VERSION 5.7 ;
  NOWIREEXTENSIONATPIN ON ;
  DIVIDERCHAR "/" ;
  BUSBITCHARS "[]" ;
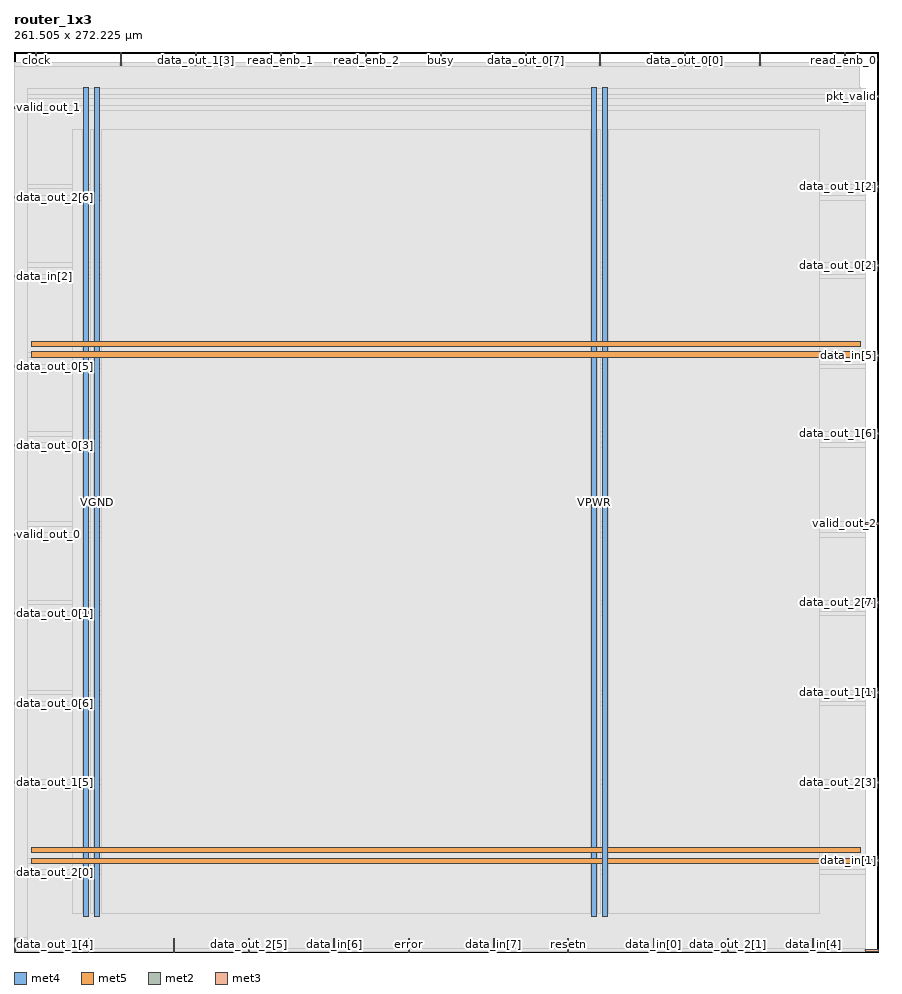
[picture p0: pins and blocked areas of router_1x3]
MACRO router_1x3
  CLASS BLOCK ;
  FOREIGN router_1x3 ;
  ORIGIN 0.000 0.000 ;
  SIZE 261.505 BY 272.225 ;
  PIN VGND
    DIRECTION INOUT ;
    USE GROUND ;
    PORT
      LAYER met4 ;
        RECT 24.340 10.640 25.940 261.360 ;
    END
    PORT
      LAYER met4 ;
        RECT 177.940 10.640 179.540 261.360 ;
    END
    PORT
      LAYER met5 ;
        RECT 5.280 30.030 256.000 31.630 ;
    END
    PORT
      LAYER met5 ;
        RECT 5.280 183.210 256.000 184.810 ;
    END
  END VGND
  PIN VPWR
    DIRECTION INOUT ;
    USE POWER ;
    PORT
      LAYER met4 ;
        RECT 21.040 10.640 22.640 261.360 ;
    END
    PORT
      LAYER met4 ;
        RECT 174.640 10.640 176.240 261.360 ;
    END
    PORT
      LAYER met5 ;
        RECT 5.280 26.730 256.000 28.330 ;
    END
    PORT
      LAYER met5 ;
        RECT 5.280 179.910 256.000 181.510 ;
    END
  END VPWR
  PIN busy
    DIRECTION OUTPUT TRISTATE ;
    USE SIGNAL ;
    ANTENNADIFFAREA 0.795200 ;
    PORT
      LAYER met2 ;
        RECT 128.890 268.225 129.170 272.225 ;
    END
  END busy
  PIN clock
    DIRECTION INPUT ;
    USE SIGNAL ;
    ANTENNAGATEAREA 0.852000 ;
    PORT
      LAYER met2 ;
        RECT 6.530 268.225 6.810 272.225 ;
    END
  END clock
  PIN data_in[0]
    DIRECTION INPUT ;
    USE SIGNAL ;
    ANTENNAGATEAREA 0.213000 ;
    PORT
      LAYER met2 ;
        RECT 193.290 0.000 193.570 4.000 ;
    END
  END data_in[0]
  PIN data_in[1]
    DIRECTION INPUT ;
    USE SIGNAL ;
    ANTENNAGATEAREA 0.213000 ;
    PORT
      LAYER met3 ;
        RECT 257.505 27.240 261.505 27.840 ;
    END
  END data_in[1]
  PIN data_in[2]
    DIRECTION INPUT ;
    USE SIGNAL ;
    ANTENNAGATEAREA 0.213000 ;
    PORT
      LAYER met3 ;
        RECT 0.000 204.040 4.000 204.640 ;
    END
  END data_in[2]
  PIN data_in[3]
    DIRECTION INPUT ;
    USE SIGNAL ;
    ANTENNAGATEAREA 0.213000 ;
    PORT
      LAYER met3 ;
        RECT 257.505 0.040 261.505 0.640 ;
    END
  END data_in[3]
  PIN data_in[4]
    DIRECTION INPUT ;
    USE SIGNAL ;
    ANTENNAGATEAREA 0.213000 ;
    PORT
      LAYER met2 ;
        RECT 241.590 0.000 241.870 4.000 ;
    END
  END data_in[4]
  PIN data_in[5]
    DIRECTION INPUT ;
    USE SIGNAL ;
    ANTENNAGATEAREA 0.159000 ;
    PORT
      LAYER met3 ;
        RECT 257.505 180.240 261.505 180.840 ;
    END
  END data_in[5]
  PIN data_in[6]
    DIRECTION INPUT ;
    USE SIGNAL ;
    ANTENNAGATEAREA 0.159000 ;
    PORT
      LAYER met2 ;
        RECT 96.690 0.000 96.970 4.000 ;
    END
  END data_in[6]
  PIN data_in[7]
    DIRECTION INPUT ;
    USE SIGNAL ;
    ANTENNAGATEAREA 0.159000 ;
    PORT
      LAYER met2 ;
        RECT 144.990 0.000 145.270 4.000 ;
    END
  END data_in[7]
  PIN data_out_0[0]
    DIRECTION OUTPUT TRISTATE ;
    USE SIGNAL ;
    ANTENNADIFFAREA 0.795200 ;
    PORT
      LAYER met2 ;
        RECT 202.950 268.225 203.230 272.225 ;
    END
  END data_out_0[0]
  PIN data_out_0[1]
    DIRECTION OUTPUT TRISTATE ;
    USE SIGNAL ;
    ANTENNADIFFAREA 0.795200 ;
    PORT
      LAYER met3 ;
        RECT 0.000 102.040 4.000 102.640 ;
    END
  END data_out_0[1]
  PIN data_out_0[2]
    DIRECTION OUTPUT TRISTATE ;
    USE SIGNAL ;
    ANTENNADIFFAREA 0.795200 ;
    PORT
      LAYER met3 ;
        RECT 257.505 207.440 261.505 208.040 ;
    END
  END data_out_0[2]
  PIN data_out_0[3]
    DIRECTION OUTPUT TRISTATE ;
    USE SIGNAL ;
    ANTENNADIFFAREA 0.795200 ;
    PORT
      LAYER met3 ;
        RECT 0.000 153.040 4.000 153.640 ;
    END
  END data_out_0[3]
  PIN data_out_0[4]
    DIRECTION OUTPUT TRISTATE ;
    USE SIGNAL ;
    ANTENNADIFFAREA 0.795200 ;
    PORT
      LAYER met2 ;
        RECT 48.390 0.000 48.670 4.000 ;
    END
  END data_out_0[4]
  PIN data_out_0[5]
    DIRECTION OUTPUT TRISTATE ;
    USE SIGNAL ;
    ANTENNADIFFAREA 0.795200 ;
    PORT
      LAYER met3 ;
        RECT 0.000 176.840 4.000 177.440 ;
    END
  END data_out_0[5]
  PIN data_out_0[6]
    DIRECTION OUTPUT TRISTATE ;
    USE SIGNAL ;
    ANTENNADIFFAREA 0.795200 ;
    PORT
      LAYER met3 ;
        RECT 0.000 74.840 4.000 75.440 ;
    END
  END data_out_0[6]
  PIN data_out_0[7]
    DIRECTION OUTPUT TRISTATE ;
    USE SIGNAL ;
    ANTENNADIFFAREA 0.795200 ;
    PORT
      LAYER met2 ;
        RECT 154.650 268.225 154.930 272.225 ;
    END
  END data_out_0[7]
  PIN data_out_1[0]
    DIRECTION OUTPUT TRISTATE ;
    USE SIGNAL ;
    ANTENNADIFFAREA 0.795200 ;
    PORT
      LAYER met2 ;
        RECT 225.490 268.225 225.770 272.225 ;
    END
  END data_out_1[0]
  PIN data_out_1[1]
    DIRECTION OUTPUT TRISTATE ;
    USE SIGNAL ;
    ANTENNADIFFAREA 0.445500 ;
    PORT
      LAYER met3 ;
        RECT 257.505 78.240 261.505 78.840 ;
    END
  END data_out_1[1]
  PIN data_out_1[2]
    DIRECTION OUTPUT TRISTATE ;
    USE SIGNAL ;
    ANTENNADIFFAREA 0.445500 ;
    PORT
      LAYER met3 ;
        RECT 257.505 231.240 261.505 231.840 ;
    END
  END data_out_1[2]
  PIN data_out_1[3]
    DIRECTION OUTPUT TRISTATE ;
    USE SIGNAL ;
    ANTENNADIFFAREA 0.795200 ;
    PORT
      LAYER met2 ;
        RECT 54.830 268.225 55.110 272.225 ;
    END
  END data_out_1[3]
  PIN data_out_1[4]
    DIRECTION OUTPUT TRISTATE ;
    USE SIGNAL ;
    ANTENNADIFFAREA 0.795200 ;
    PORT
      LAYER met2 ;
        RECT 0.090 0.000 0.370 4.000 ;
    END
  END data_out_1[4]
  PIN data_out_1[5]
    DIRECTION OUTPUT TRISTATE ;
    USE SIGNAL ;
    ANTENNADIFFAREA 0.795200 ;
    PORT
      LAYER met3 ;
        RECT 0.000 51.040 4.000 51.640 ;
    END
  END data_out_1[5]
  PIN data_out_1[6]
    DIRECTION OUTPUT TRISTATE ;
    USE SIGNAL ;
    ANTENNADIFFAREA 0.445500 ;
    PORT
      LAYER met3 ;
        RECT 257.505 156.440 261.505 157.040 ;
    END
  END data_out_1[6]
  PIN data_out_1[7]
    DIRECTION OUTPUT TRISTATE ;
    USE SIGNAL ;
    ANTENNADIFFAREA 0.795200 ;
    PORT
      LAYER met2 ;
        RECT 32.290 268.225 32.570 272.225 ;
    END
  END data_out_1[7]
  PIN data_out_2[0]
    DIRECTION OUTPUT TRISTATE ;
    USE SIGNAL ;
    ANTENNADIFFAREA 0.795200 ;
    PORT
      LAYER met3 ;
        RECT 0.000 23.840 4.000 24.440 ;
    END
  END data_out_2[0]
  PIN data_out_2[1]
    DIRECTION OUTPUT TRISTATE ;
    USE SIGNAL ;
    ANTENNADIFFAREA 0.795200 ;
    PORT
      LAYER met2 ;
        RECT 215.830 0.000 216.110 4.000 ;
    END
  END data_out_2[1]
  PIN data_out_2[2]
    DIRECTION OUTPUT TRISTATE ;
    USE SIGNAL ;
    ANTENNADIFFAREA 0.795200 ;
    PORT
      LAYER met2 ;
        RECT 177.190 268.225 177.470 272.225 ;
    END
  END data_out_2[2]
  PIN data_out_2[3]
    DIRECTION OUTPUT TRISTATE ;
    USE SIGNAL ;
    ANTENNADIFFAREA 0.445500 ;
    PORT
      LAYER met3 ;
        RECT 257.505 51.040 261.505 51.640 ;
    END
  END data_out_2[3]
  PIN data_out_2[4]
    DIRECTION OUTPUT TRISTATE ;
    USE SIGNAL ;
    ANTENNADIFFAREA 0.795200 ;
    PORT
      LAYER met2 ;
        RECT 22.630 0.000 22.910 4.000 ;
    END
  END data_out_2[4]
  PIN data_out_2[5]
    DIRECTION OUTPUT TRISTATE ;
    USE SIGNAL ;
    ANTENNADIFFAREA 0.795200 ;
    PORT
      LAYER met2 ;
        RECT 70.930 0.000 71.210 4.000 ;
    END
  END data_out_2[5]
  PIN data_out_2[6]
    DIRECTION OUTPUT TRISTATE ;
    USE SIGNAL ;
    ANTENNADIFFAREA 0.795200 ;
    PORT
      LAYER met3 ;
        RECT 0.000 227.840 4.000 228.440 ;
    END
  END data_out_2[6]
  PIN data_out_2[7]
    DIRECTION OUTPUT TRISTATE ;
    USE SIGNAL ;
    ANTENNADIFFAREA 0.445500 ;
    PORT
      LAYER met3 ;
        RECT 257.505 105.440 261.505 106.040 ;
    END
  END data_out_2[7]
  PIN error
    DIRECTION OUTPUT TRISTATE ;
    USE SIGNAL ;
    ANTENNADIFFAREA 0.795200 ;
    PORT
      LAYER met2 ;
        RECT 119.230 0.000 119.510 4.000 ;
    END
  END error
  PIN pkt_valid
    DIRECTION INPUT ;
    USE SIGNAL ;
    ANTENNAGATEAREA 0.213000 ;
    PORT
      LAYER met3 ;
        RECT 257.505 258.440 261.505 259.040 ;
    END
  END pkt_valid
  PIN read_enb_0
    DIRECTION INPUT ;
    USE SIGNAL ;
    ANTENNAGATEAREA 0.213000 ;
    PORT
      LAYER met2 ;
        RECT 251.250 268.225 251.530 272.225 ;
    END
  END read_enb_0
  PIN read_enb_1
    DIRECTION INPUT ;
    USE SIGNAL ;
    ANTENNAGATEAREA 0.213000 ;
    PORT
      LAYER met2 ;
        RECT 80.590 268.225 80.870 272.225 ;
    END
  END read_enb_1
  PIN read_enb_2
    DIRECTION INPUT ;
    USE SIGNAL ;
    ANTENNAGATEAREA 0.213000 ;
    PORT
      LAYER met2 ;
        RECT 106.350 268.225 106.630 272.225 ;
    END
  END read_enb_2
  PIN resetn
    DIRECTION INPUT ;
    USE SIGNAL ;
    ANTENNAGATEAREA 0.159000 ;
    PORT
      LAYER met2 ;
        RECT 167.530 0.000 167.810 4.000 ;
    END
  END resetn
  PIN valid_out_0
    DIRECTION OUTPUT TRISTATE ;
    USE SIGNAL ;
    ANTENNADIFFAREA 0.795200 ;
    PORT
      LAYER met3 ;
        RECT 0.000 125.840 4.000 126.440 ;
    END
  END valid_out_0
  PIN valid_out_1
    DIRECTION OUTPUT TRISTATE ;
    USE SIGNAL ;
    ANTENNADIFFAREA 0.795200 ;
    PORT
      LAYER met3 ;
        RECT 0.000 255.040 4.000 255.640 ;
    END
  END valid_out_1
  PIN valid_out_2
    DIRECTION OUTPUT TRISTATE ;
    USE SIGNAL ;
    ANTENNADIFFAREA 0.795200 ;
    PORT
      LAYER met3 ;
        RECT 257.505 129.240 261.505 129.840 ;
    END
  END valid_out_2
  OBS
      LAYER li1 ;
        RECT 5.520 10.795 255.760 261.205 ;
      LAYER met1 ;
        RECT 0.070 10.640 256.060 261.360 ;
      LAYER met2 ;
        RECT 0.100 267.945 6.250 269.010 ;
        RECT 7.090 267.945 32.010 269.010 ;
        RECT 32.850 267.945 54.550 269.010 ;
        RECT 55.390 267.945 80.310 269.010 ;
        RECT 81.150 267.945 106.070 269.010 ;
        RECT 106.910 267.945 128.610 269.010 ;
        RECT 129.450 267.945 154.370 269.010 ;
        RECT 155.210 267.945 176.910 269.010 ;
        RECT 177.750 267.945 202.670 269.010 ;
        RECT 203.510 267.945 225.210 269.010 ;
        RECT 226.050 267.945 250.970 269.010 ;
        RECT 251.810 267.945 255.670 269.010 ;
        RECT 0.100 4.280 255.670 267.945 ;
        RECT 0.650 0.155 22.350 4.280 ;
        RECT 23.190 0.155 48.110 4.280 ;
        RECT 48.950 0.155 70.650 4.280 ;
        RECT 71.490 0.155 96.410 4.280 ;
        RECT 97.250 0.155 118.950 4.280 ;
        RECT 119.790 0.155 144.710 4.280 ;
        RECT 145.550 0.155 167.250 4.280 ;
        RECT 168.090 0.155 193.010 4.280 ;
        RECT 193.850 0.155 215.550 4.280 ;
        RECT 216.390 0.155 241.310 4.280 ;
        RECT 242.150 0.155 255.670 4.280 ;
      LAYER met3 ;
        RECT 3.990 259.440 257.505 261.285 ;
        RECT 3.990 258.040 257.105 259.440 ;
        RECT 3.990 256.040 257.505 258.040 ;
        RECT 4.400 254.640 257.505 256.040 ;
        RECT 3.990 232.240 257.505 254.640 ;
        RECT 3.990 230.840 257.105 232.240 ;
        RECT 3.990 228.840 257.505 230.840 ;
        RECT 4.400 227.440 257.505 228.840 ;
        RECT 3.990 208.440 257.505 227.440 ;
        RECT 3.990 207.040 257.105 208.440 ;
        RECT 3.990 205.040 257.505 207.040 ;
        RECT 4.400 203.640 257.505 205.040 ;
        RECT 3.990 181.240 257.505 203.640 ;
        RECT 3.990 179.840 257.105 181.240 ;
        RECT 3.990 177.840 257.505 179.840 ;
        RECT 4.400 176.440 257.505 177.840 ;
        RECT 3.990 157.440 257.505 176.440 ;
        RECT 3.990 156.040 257.105 157.440 ;
        RECT 3.990 154.040 257.505 156.040 ;
        RECT 4.400 152.640 257.505 154.040 ;
        RECT 3.990 130.240 257.505 152.640 ;
        RECT 3.990 128.840 257.105 130.240 ;
        RECT 3.990 126.840 257.505 128.840 ;
        RECT 4.400 125.440 257.505 126.840 ;
        RECT 3.990 106.440 257.505 125.440 ;
        RECT 3.990 105.040 257.105 106.440 ;
        RECT 3.990 103.040 257.505 105.040 ;
        RECT 4.400 101.640 257.505 103.040 ;
        RECT 3.990 79.240 257.505 101.640 ;
        RECT 3.990 77.840 257.105 79.240 ;
        RECT 3.990 75.840 257.505 77.840 ;
        RECT 4.400 74.440 257.505 75.840 ;
        RECT 3.990 52.040 257.505 74.440 ;
        RECT 4.400 50.640 257.105 52.040 ;
        RECT 3.990 28.240 257.505 50.640 ;
        RECT 3.990 26.840 257.105 28.240 ;
        RECT 3.990 24.840 257.505 26.840 ;
        RECT 4.400 23.440 257.505 24.840 ;
        RECT 3.990 1.040 257.505 23.440 ;
        RECT 3.990 0.175 257.105 1.040 ;
      LAYER met4 ;
        RECT 17.775 11.735 20.640 248.705 ;
        RECT 23.040 11.735 23.940 248.705 ;
        RECT 26.340 11.735 174.240 248.705 ;
        RECT 176.640 11.735 177.540 248.705 ;
        RECT 179.940 11.735 243.505 248.705 ;
  END
END router_1x3
END LIBRARY

